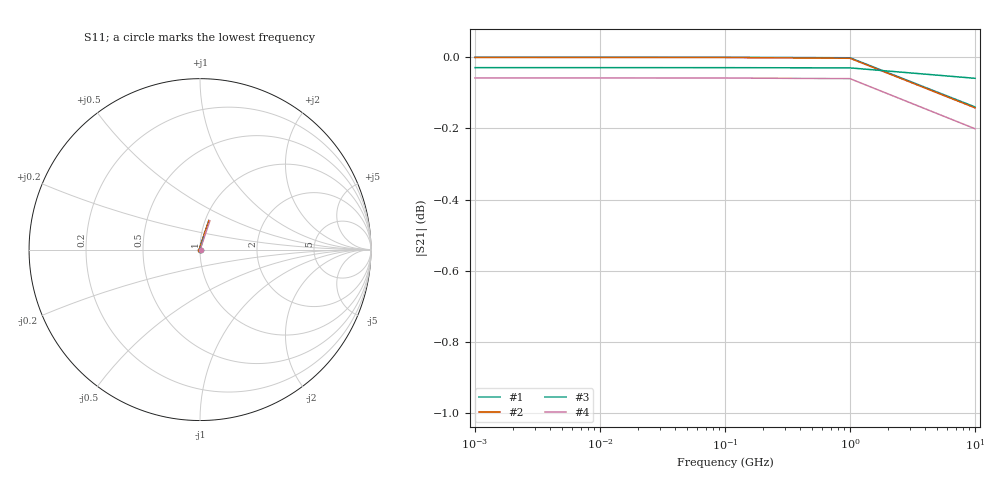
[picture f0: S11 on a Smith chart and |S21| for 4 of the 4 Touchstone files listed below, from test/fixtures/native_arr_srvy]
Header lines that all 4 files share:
! Sonnet Data File
! From: em Version : 18.53-Lite
! Data is NOT De-embedded
# GHZ S RI R 50.00000
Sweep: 1 MHz to 10 GHz
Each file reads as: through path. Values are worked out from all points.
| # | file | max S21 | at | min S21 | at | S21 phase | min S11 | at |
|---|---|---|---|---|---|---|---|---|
| 1 | ac_INF.native.s2p | 0.00 dB | 1 MHz | -0.1 dB | 10 GHz | -0 deg at 100 MHz | -94.7 dB | 1 MHz |
| 2 | ad_1_1_SRVY.native.s2p | 0.00 dB | 1 MHz | -0.1 dB | 10 GHz | -0 deg at 100 MHz | -82.9 dB | 1 MHz |
| 3 | ah_srvy.native.s2p | -0.03 dB | 1 MHz | -0.1 dB | 10 GHz | -0 deg at 100 MHz | -49.5 dB | 1 MHz |
| 4 | an__5__01_SRVY.native.s2p | -0.06 dB | 1 MHz | -0.2 dB | 10 GHz | -0 deg at 100 MHz | -43.5 dB | 1 MHz |
